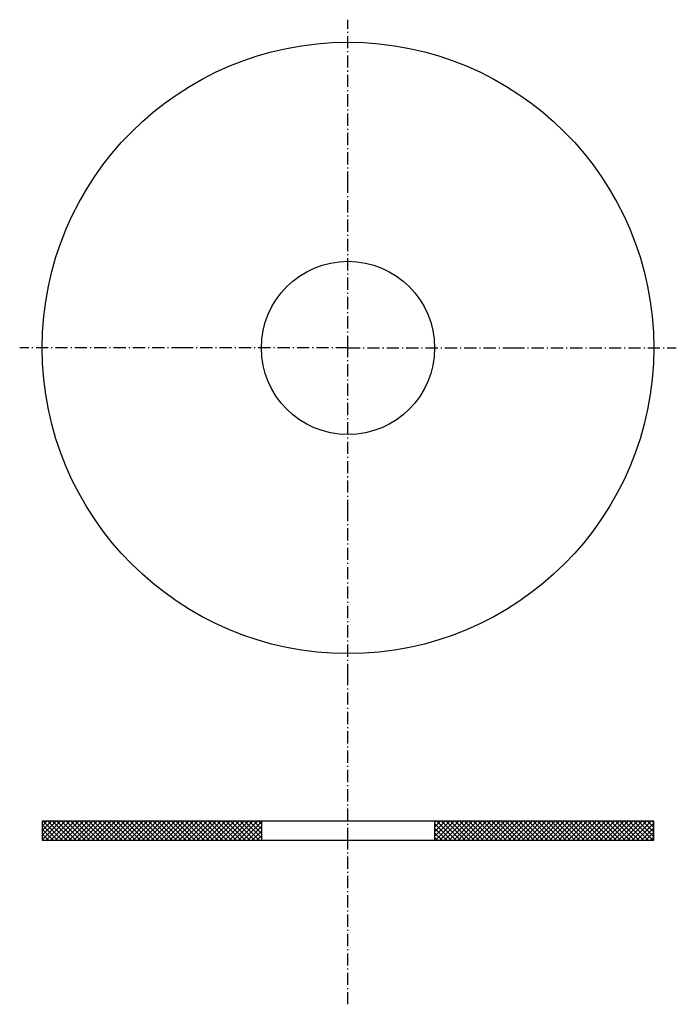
# Model space of a CAD drawing. Units: millimetres. Extents: x -7.9 to 56.5, y -7.9 to 88.7.
import ezdxf

# ---------------------------------------------------------------- set-up
doc = ezdxf.new("R2010")
doc.units = ezdxf.units.MM
doc.header["$LTSCALE"] = 0.4
doc.linetypes.add('ACAD_ISO10W100', pattern=[18, 12, -3, 0, -3])

msp = doc.modelspace()

# ---------------------------------------------------------------- hatches: boundary and pattern name
at = {"lineweight": 15, "ltscale": 0.25}
h = msp.add_hatch(dxfattribs=at)
h.set_pattern_fill('ANSI37', scale=0.1, style=0)
h.paths.add_polyline_path([(15.826, 10.06), (-5.674, 10.06), (-5.674, 8.2), (15.826, 8.2)])
h = msp.add_hatch(dxfattribs=at)
h.set_pattern_fill('ANSI37', scale=0.1, style=0)
h.paths.add_polyline_path([(54.326, 10.06), (32.826, 10.06), (32.826, 8.2), (54.326, 8.2)])

# ---------------------------------------------------------------- linework, layer by layer
at = {"color": 1, "linetype": 'ACAD_ISO10W100', "lineweight": 25, "ltscale": 0.25}
for p, q in [((24.326, 72.606), (24.326, 88.707)), ((24.326, 56.504), (24.326, 72.606)), ((8.224, 56.504), (-7.877, 56.504)), ((24.326, 56.504), (8.224, 56.504)), ((24.326, 40.403), (24.326, 56.504)), ((24.326, 56.504), (40.428, 56.504)), ((40.428, 56.504), (56.529, 56.504)), ((24.326, 24.301), (24.326, 40.403)), ((24.326, 8.2), (24.326, 24.301)), ((24.326, -7.902), (24.326, 8.2))]:
    msp.add_line(p, q, dxfattribs=at)
at = {"color": 7, "lineweight": 30, "ltscale": 0.25}
for p, q in [((54.326, 10.06), (-5.674, 10.06)), ((-5.674, 10.06), (-5.674, 8.2)), ((15.826, 10.06), (15.826, 8.2)), ((32.826, 10.06), (32.826, 8.2)), ((54.326, 8.2), (54.326, 10.06)), ((-5.674, 8.2), (54.326, 8.2))]:
    msp.add_line(p, q, dxfattribs=at)
at = {"color": 7, "lineweight": 15, "ltscale": 0.25}
for p, q in [((-5.674, 10.06), (-5.674, 8.2)), ((15.826, 10.06), (-5.674, 10.06)), ((15.826, 8.2), (15.826, 10.06)), ((-5.674, 8.2), (15.826, 8.2))]:
    msp.add_line(p, q, dxfattribs=at)
at = {"color": 7, "lineweight": 30, "ltscale": 0.25}
for radius in [30, 8.5]:
    msp.add_circle((24.326, 56.504), radius, dxfattribs=at)

doc.saveas('drawing.dxf')
